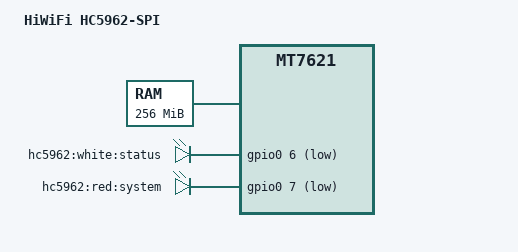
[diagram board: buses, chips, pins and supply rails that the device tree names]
/dts-v1/;

#include "mt7621.dtsi"

#include <dt-bindings/gpio/gpio.h>
#include <dt-bindings/input/input.h>

/ {
	compatible = "hiwifi,hc5962-spi", "mediatek,mt7621-soc";
	model = "HiWiFi HC5962-SPI";

	aliases {
		led-boot = &led_system;
		led-failsafe = &led_system;
		led-running = &led_status;
		led-upgrade = &led_status;
	};
	
	memory@0 {
		device_type = "memory";
		reg = <0x0 0x10000000>;
	};

	chosen {
		bootargs = "console=ttyS0,115200";
	};

	leds {
		compatible = "gpio-leds";

		led_status: status {
			label = "hc5962:white:status";
			gpios = <&gpio0 6 GPIO_ACTIVE_LOW>;
		};

		led_system: system {
			label = "hc5962:red:system";
			gpios = <&gpio0 7 GPIO_ACTIVE_LOW>;
			panic-indicator;
		};
	};

	keys {
